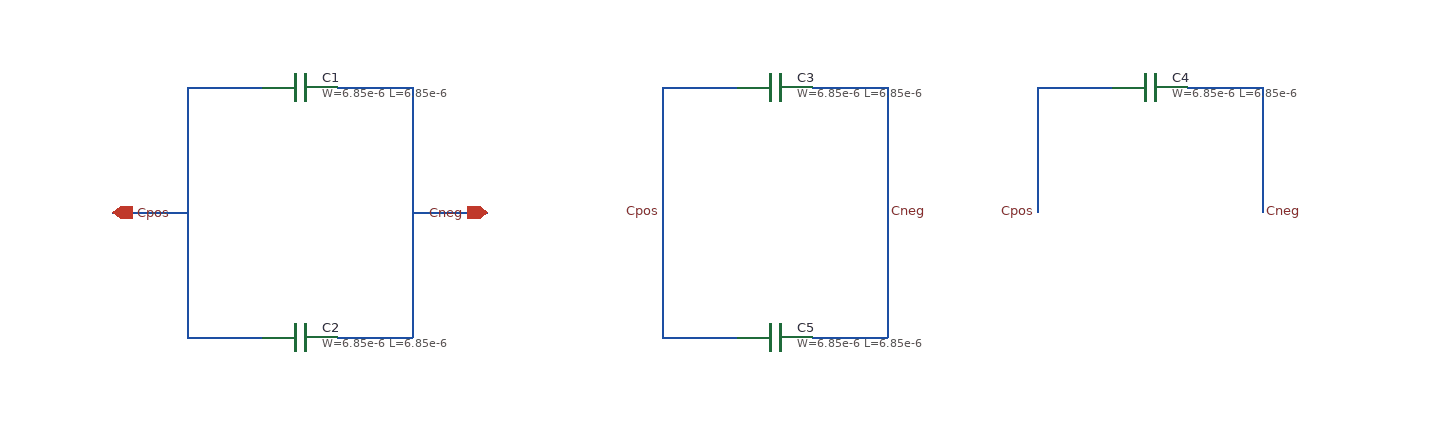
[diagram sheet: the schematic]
v {xschem version=3.4.8RC file_version=1.3}
G {}
K {}
V {}
S {}
F {}
E {}
N 720 -450 780 -450 {lab=Cneg}
N 600 -450 660 -450 {lab=Cpos}
N 600 -250 660 -250 {lab=Cpos}
N 720 -250 780 -250 {lab=Cneg}
N 340 -450 400 -450 {lab=Cneg}
N 220 -450 280 -450 {lab=Cpos}
N 220 -250 280 -250 {lab=Cpos}
N 340 -250 400 -250 {lab=Cneg}
N 400 -450 400 -250 {lab=Cneg}
N 220 -450 220 -250 {lab=Cpos}
N 160 -350 220 -350 {lab=Cpos}
N 400 -350 460 -350 {lab=Cneg}
N 600 -450 600 -250 {lab=Cpos}
N 780 -450 780 -250 {lab=Cneg}
N 1020 -450 1080 -450 {lab=Cneg}
N 900 -450 960 -450 {lab=Cpos}
N 900 -450 900 -350 {lab=Cpos}
N 1080 -450 1080 -350 {lab=Cneg}
C {iopin.sym} 160 -350 0 1 {name=p3 lab=Cpos}
C {iopin.sym} 460 -350 0 0 {name=p4 lab=Cneg}
C {lab_pin.sym} 600 -350 0 0 {name=p20 lab=Cpos}
C {lab_pin.sym} 780 -350 0 1 {name=p5 lab=Cneg}
C {lab_pin.sym} 900 -350 0 0 {name=p1 lab=Cpos}
C {lab_pin.sym} 1080 -350 0 1 {name=p2 lab=Cneg}
C {symbols/cap_mim_2f0fF.sym} 310 -450 3 0 {name=C1
W=6.85e-6
L=6.85e-6
model=cap_mim_2f0fF
spiceprefix=X
m=1}
C {title.sym} 180 -50 0 0 {name=l1 author="Sayyad Arif"}
C {symbols/cap_mim_2f0fF.sym} 310 -250 3 0 {name=C2
W=6.85e-6
L=6.85e-6
model=cap_mim_2f0fF
spiceprefix=X
m=1}
C {symbols/cap_mim_2f0fF.sym} 690 -450 3 0 {name=C3
W=6.85e-6
L=6.85e-6
model=cap_mim_2f0fF
spiceprefix=X
m=1}
C {symbols/cap_mim_2f0fF.sym} 990 -450 3 0 {name=C4
W=6.85e-6
L=6.85e-6
model=cap_mim_2f0fF
spiceprefix=X
m=1}
C {symbols/cap_mim_2f0fF.sym} 690 -250 3 0 {name=C5
W=6.85e-6
L=6.85e-6
model=cap_mim_2f0fF
spiceprefix=X
m=1}
